One B-rep face of a CAD part: STEP entity #2239.
In plain terms, the planar face has unit normal (1, 0, 0).
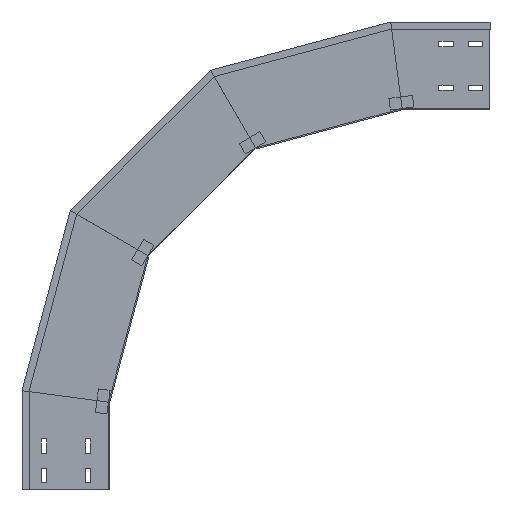
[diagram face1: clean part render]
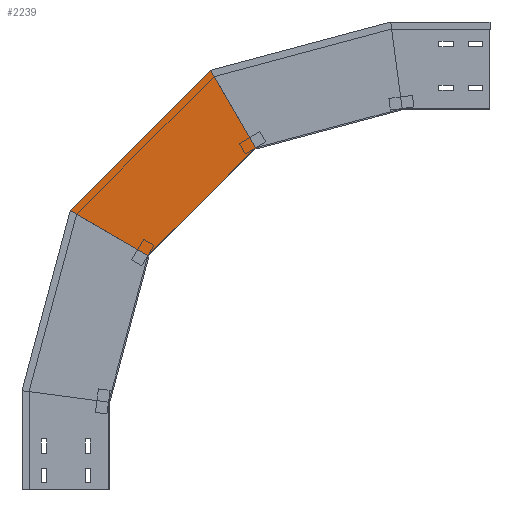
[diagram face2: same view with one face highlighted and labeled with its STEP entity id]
Its self-contained STEP definition (entity closure, numbers rounded to 3 decimals):
#13 = PLANE ( 'NONE',  #1455 ) ;
#38 = VERTEX_POINT ( 'NONE', #1918 ) ;
#86 = LINE ( 'NONE', #1966, #1635 ) ;
#314 = LINE ( 'NONE', #682, #1141 ) ;
#355 = DIRECTION ( 'NONE',  ( 0., -0.866, -0.5 ) ) ;
#441 = CARTESIAN_POINT ( 'NONE',  ( 0., -35.701, 368.842 ) ) ;
#532 = LINE ( 'NONE', #1668, #2263 ) ;
#597 = FACE_OUTER_BOUND ( 'NONE', #1509, .T. ) ;
#630 = ORIENTED_EDGE ( 'NONE', *, *, #949, .F. ) ;
#682 = CARTESIAN_POINT ( 'NONE',  ( 0., 70.365, 474.908 ) ) ;
#684 = ORIENTED_EDGE ( 'NONE', *, *, #1670, .T. ) ;
#753 = ORIENTED_EDGE ( 'NONE', *, *, #1958, .F. ) ;
#877 = EDGE_CURVE ( 'NONE', #2041, #38, #86, .T. ) ;
#878 = CARTESIAN_POINT ( 'NONE',  ( 0., -35.701, 368.842 ) ) ;
#949 = EDGE_CURVE ( 'NONE', #1083, #2374, #532, .T. ) ;
#1083 = VERTEX_POINT ( 'NONE', #1920 ) ;
#1136 = DIRECTION ( 'NONE',  ( 0., 0., -1. ) ) ;
#1141 = VECTOR ( 'NONE', #1461, 1000. ) ;
#1181 = VECTOR ( 'NONE', #2007, 1000. ) ;
#1196 = CARTESIAN_POINT ( 'NONE',  ( 0., -67.034, 400.175 ) ) ;
#1455 = AXIS2_PLACEMENT_3D ( 'NONE', #441, #2162, #1136 ) ;
#1461 = DIRECTION ( 'NONE',  ( 0., -0.707, 0.707 ) ) ;
#1509 = EDGE_LOOP ( 'NONE', ( #684, #1584, #753, #630 ) ) ;
#1584 = ORIENTED_EDGE ( 'NONE', *, *, #877, .T. ) ;
#1635 = VECTOR ( 'NONE', #2014, 1000. ) ;
#1668 = CARTESIAN_POINT ( 'NONE',  ( 0., -129.979, 363.834 ) ) ;
#1670 = EDGE_CURVE ( 'NONE', #1083, #2041, #314, .T. ) ;
#1823 = LINE ( 'NONE', #878, #1181 ) ;
#1918 = CARTESIAN_POINT ( 'NONE',  ( 0., -250.175, 583.315 ) ) ;
#1920 = CARTESIAN_POINT ( 'NONE',  ( 0., 67.452, 477.821 ) ) ;
#1958 = EDGE_CURVE ( 'NONE', #2374, #38, #1823, .T. ) ;
#1966 = CARTESIAN_POINT ( 'NONE',  ( 0., -289.426, 515.33 ) ) ;
#2007 = DIRECTION ( 'NONE',  ( 0., -0.707, 0.707 ) ) ;
#2014 = DIRECTION ( 'NONE',  ( 0., -0.5, -0.866 ) ) ;
#2022 = CARTESIAN_POINT ( 'NONE',  ( 0., -172.529, 717.802 ) ) ;
#2041 = VERTEX_POINT ( 'NONE', #2022 ) ;
#2162 = DIRECTION ( 'NONE',  ( 1., 0., 0. ) ) ;
#2239 = ADVANCED_FACE ( 'NONE', ( #597 ), #13, .T. ) ;
#2263 = VECTOR ( 'NONE', #355, 1000. ) ;
#2374 = VERTEX_POINT ( 'NONE', #1196 ) ;
